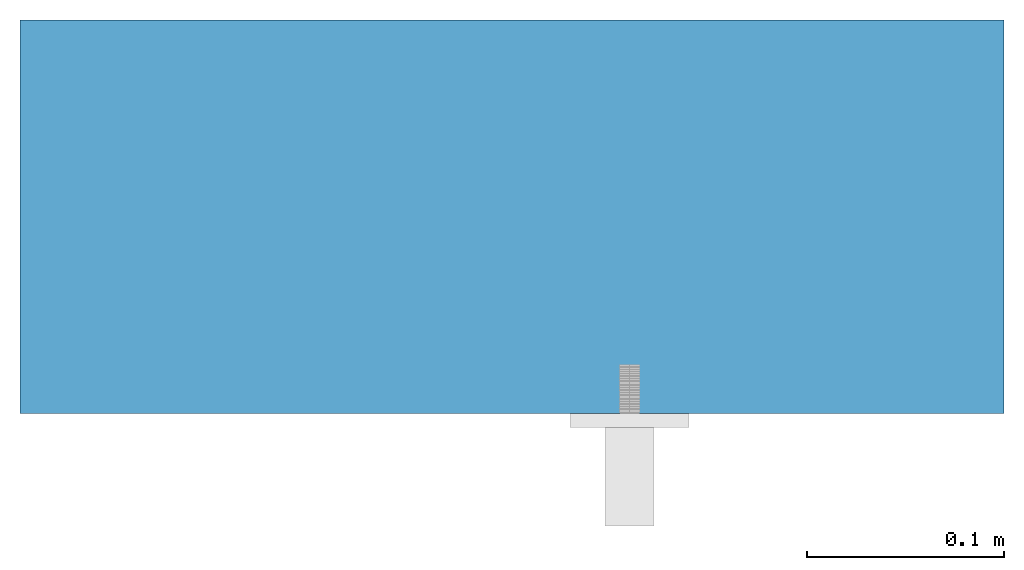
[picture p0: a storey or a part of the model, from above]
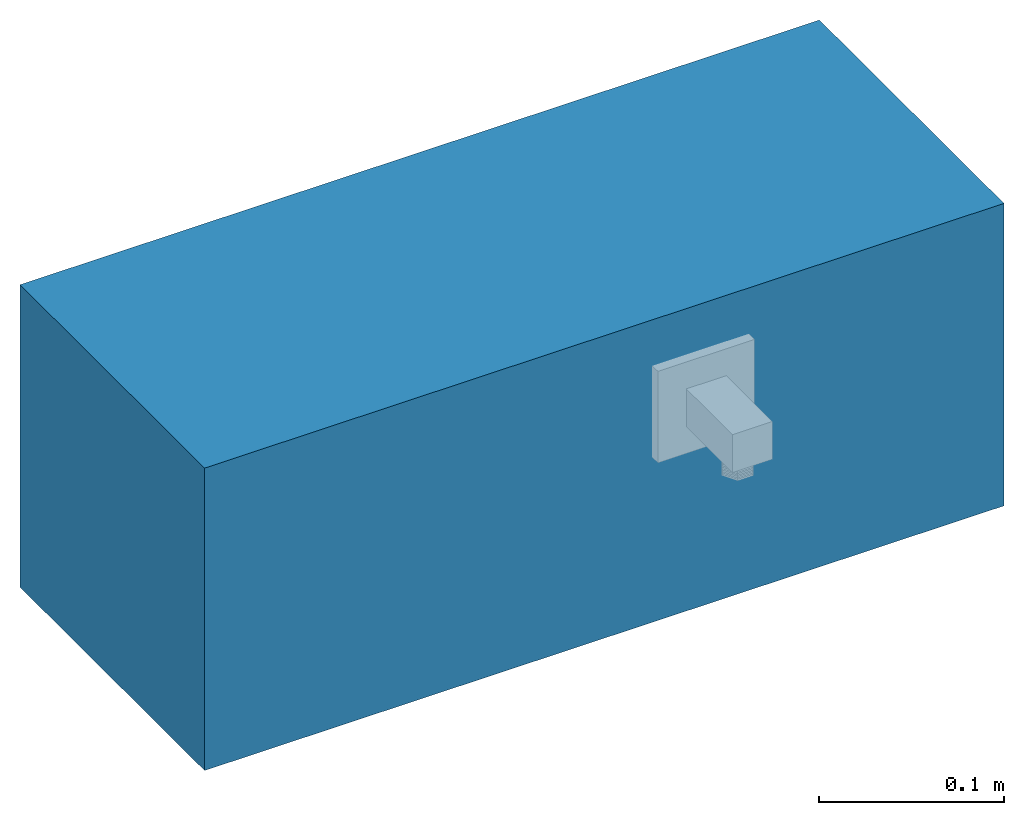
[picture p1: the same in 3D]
Properties of the parts of a building model (IFC2X3)

# File
Description: ViewDefinition [CoordinationView_V2.0]
File name: Project Number
Time: 2021-09-29T10:22:48
Written by: The EXPRESS Data Manager Version 5.02.0100.07 : 28 Aug 2013
Made in: 20190108_1515(x64) - Exporter 19.2.1.1 - Alternate UI 19.2.1.1
Comment: STEP Physical File produced by: The EXPRESS Data Manager Version 5.02.0100.07 : 28 Aug 2013 * Module: EDMstepFileFactory/EDMstandAlone * Creation date: Wed Sep 29 10:22:48 2021 * Host: DESKTOP-OPR7GPE * Database: C:\Users\ABLESU~1\AppData\Local\Temp\{9EC4D3DA-2B9B-4F1A-BCB7-34000E6AD5EF}\ifc * Database version: 5507 * Database creation date: Wed Sep 29 10:22:47 2021 * Schema: IFC2X3 * Model: DataRepository.ifc * Model creation date: Wed Sep 29 10:22:48 2021 * Header model: DataRepository.ifc_HeaderModel * Header model creation date: Wed Sep 29 10:22:48 2021 * EDMuser: sdai-user * EDMgroup: sdai-group * License ID and type: 5605 : Permanent license. Expiry date: * EDMstepFileFactory options: 020000

# IfcProject, Project Number
LongName: Project Name; Phase: Project Status

# IfcSite, Default
RefLatitude: 42, 12, 46, 799999; RefLongitude: -71, -1, -58, -799999; RefElevation: 0 mm

# IfcBuilding
Pset_BuildingCommon - NumberOfStoreys: 1

# IfcBuildingStorey, Level 1
LongName: Level 1; Elevation: 0 mm

# IfcFlowTerminal: Square Wall Outlet (G1/2") FFAS9142-000500BC0, American Standard Shower Accessories EasySET Square Wall Outlet (G1-2):Square Wall Outlet (G1/2") FFAS9142-000500BC0:917896
In: Level 1
Material: Chrome
Pset_ManufacturerTypeInformation - Manufacturer: American Standard
Pset_DistributionFlowElementCommon - Reference: Square Wall Outlet (G1/2") FFAS9142-000500BC0

# IfcWallStandardCase: Basic Wall:Generic - 200mm, Basic Wall:Generic - 200mm:916791
In: Level 1
Type - PredefinedType: STANDARD; Material: Default Wall 200 mm
Pset_WallCommon - Reference: Generic - 200mm; LoadBearing: no; ExtendToStructure: no; IsExternal: yes
